VERSION 5.7 ;
  DIVIDERCHAR "/" ;
  BUSBITCHARS "[]" ;
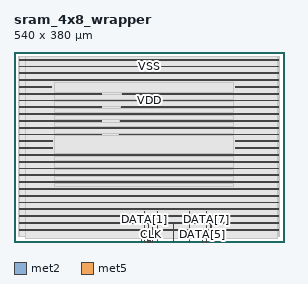
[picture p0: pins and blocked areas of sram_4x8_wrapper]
MACRO sram_4x8_wrapper
  CLASS BLOCK ;
  FOREIGN sram_4x8_wrapper ;
  ORIGIN 0.000 0.000 ;
  SIZE 540.000 BY 380.000 ;
  PIN ADDR[0]
    ANTENNAGATEAREA 0.126000 ;
    DIRECTION INPUT ;
    USE SIGNAL ;
    PORT
      LAYER met2 ;
        RECT 276.160 0.000 276.300 49.680 ;
    END
  END ADDR[0]
  PIN ADDR[1]
    ANTENNAGATEAREA 0.126000 ;
    DIRECTION INPUT ;
    USE SIGNAL ;
    PORT
      LAYER met2 ;
        RECT 269.720 0.000 269.860 49.340 ;
    END
  END ADDR[1]
  PIN CLK
    ANTENNAGATEAREA 2.733000 ;
    DIRECTION INPUT ;
    USE CLOCK ;
    PORT
      LAYER met2 ;
        RECT 273.400 0.000 273.540 6.320 ;
    END
  END CLK
  PIN CSb
    ANTENNAGATEAREA 0.495000 ;
    DIRECTION INPUT ;
    USE SIGNAL ;
    PORT
      LAYER met2 ;
        RECT 270.640 0.000 270.780 12.280 ;
    END
  END CSb
  PIN DATA[0]
    ANTENNAGATEAREA 0.126000 ;
    ANTENNADIFFAREA 1.782000 ;
    DIRECTION INOUT ;
    USE SIGNAL ;
    PORT
      LAYER met2 ;
        RECT 254.080 0.000 254.220 12.650 ;
    END
  END DATA[0]
  PIN DATA[1]
    ANTENNAGATEAREA 0.126000 ;
    ANTENNADIFFAREA 1.782000 ;
    DIRECTION INOUT ;
    USE SIGNAL ;
    PORT
      LAYER met2 ;
        RECT 260.060 0.000 260.200 60.560 ;
    END
  END DATA[1]
  PIN DATA[2]
    ANTENNAGATEAREA 0.126000 ;
    ANTENNADIFFAREA 1.782000 ;
    DIRECTION INOUT ;
    USE SIGNAL ;
    PORT
      LAYER met2 ;
        RECT 286.740 0.000 286.880 61.240 ;
    END
  END DATA[2]
  PIN DATA[3]
    ANTENNAGATEAREA 0.126000 ;
    ANTENNADIFFAREA 1.782000 ;
    DIRECTION INOUT ;
    USE SIGNAL ;
    PORT
      LAYER met2 ;
        RECT 318.940 0.000 319.080 36.420 ;
    END
  END DATA[3]
  PIN DATA[4]
    ANTENNAGATEAREA 0.126000 ;
    ANTENNADIFFAREA 1.782000 ;
    DIRECTION INOUT ;
    USE SIGNAL ;
    PORT
      LAYER met2 ;
        RECT 351.140 0.000 351.280 60.560 ;
    END
  END DATA[4]
  PIN DATA[5]
    ANTENNAGATEAREA 0.126000 ;
    ANTENNADIFFAREA 1.782000 ;
    DIRECTION INOUT ;
    USE SIGNAL ;
    PORT
      LAYER met2 ;
        RECT 376.900 0.000 377.040 9.930 ;
    END
  END DATA[5]
  PIN DATA[6]
    ANTENNAGATEAREA 0.126000 ;
    ANTENNADIFFAREA 1.782000 ;
    DIRECTION INOUT ;
    USE SIGNAL ;
    PORT
      LAYER met2 ;
        RECT 393.920 0.000 394.060 50.360 ;
    END
  END DATA[6]
  PIN DATA[7]
    ANTENNAGATEAREA 0.126000 ;
    ANTENNADIFFAREA 1.782000 ;
    DIRECTION INOUT ;
    USE SIGNAL ;
    PORT
      LAYER met2 ;
        RECT 384.720 0.000 384.860 61.580 ;
    END
  END DATA[7]
  PIN OEb
    ANTENNAGATEAREA 0.373500 ;
    DIRECTION INPUT ;
    USE SIGNAL ;
    PORT
      LAYER met2 ;
        RECT 266.040 0.000 266.180 11.940 ;
    END
  END OEb
  PIN VDD
    ANTENNADIFFAREA 667.750610 ;
    DIRECTION INOUT ;
    USE POWER ;
    PORT
      LAYER met5 ;
        RECT 443.560 309.280 529.920 310.880 ;
    END
    PORT
      LAYER met5 ;
        RECT 442.600 200.480 529.920 202.080 ;
    END
    PORT
      LAYER met5 ;
        RECT 10.120 363.680 529.920 365.280 ;
    END
    PORT
      LAYER met5 ;
        RECT 10.120 336.480 529.920 338.080 ;
    END
    PORT
      LAYER met5 ;
        RECT 10.120 309.280 74.800 310.880 ;
    END
    PORT
      LAYER met5 ;
        RECT 10.120 282.080 529.920 283.680 ;
    END
    PORT
      LAYER met5 ;
        RECT 10.120 254.880 529.920 256.480 ;
    END
    PORT
      LAYER met5 ;
        RECT 10.120 227.680 529.920 229.280 ;
    END
    PORT
      LAYER met5 ;
        RECT 10.120 200.480 76.400 202.080 ;
    END
    PORT
      LAYER met5 ;
        RECT 10.120 173.280 529.920 174.880 ;
    END
    PORT
      LAYER met5 ;
        RECT 10.120 146.080 529.920 147.680 ;
    END
    PORT
      LAYER met5 ;
        RECT 10.120 118.880 529.920 120.480 ;
    END
    PORT
      LAYER met5 ;
        RECT 10.120 91.680 529.920 93.280 ;
    END
    PORT
      LAYER met5 ;
        RECT 10.120 64.480 529.920 66.080 ;
    END
    PORT
      LAYER met5 ;
        RECT 10.120 37.280 529.920 38.880 ;
    END
  END VDD
  PIN VSS
    ANTENNADIFFAREA 597.384949 ;
    DIRECTION INOUT ;
    USE GROUND ;
    PORT
      LAYER met5 ;
        RECT 442.600 186.880 529.920 188.480 ;
    END
    PORT
      LAYER met5 ;
        RECT 216.500 295.680 529.920 297.280 ;
    END
    PORT
      LAYER met5 ;
        RECT 214.500 268.480 529.920 270.080 ;
    END
    PORT
      LAYER met5 ;
        RECT 212.500 241.280 529.920 242.880 ;
    END
    PORT
      LAYER met5 ;
        RECT 210.500 214.080 529.920 215.680 ;
    END
    PORT
      LAYER met5 ;
        RECT 10.120 350.080 529.920 351.680 ;
    END
    PORT
      LAYER met5 ;
        RECT 10.120 322.880 529.920 324.480 ;
    END
    PORT
      LAYER met5 ;
        RECT 10.120 295.680 174.350 297.280 ;
    END
    PORT
      LAYER met5 ;
        RECT 10.120 268.480 174.350 270.080 ;
    END
    PORT
      LAYER met5 ;
        RECT 10.120 241.280 174.350 242.880 ;
    END
    PORT
      LAYER met5 ;
        RECT 10.120 214.080 174.350 215.680 ;
    END
    PORT
      LAYER met5 ;
        RECT 10.120 186.880 76.400 188.480 ;
    END
    PORT
      LAYER met5 ;
        RECT 10.120 159.680 529.920 161.280 ;
    END
    PORT
      LAYER met5 ;
        RECT 10.120 132.480 529.920 134.080 ;
    END
    PORT
      LAYER met5 ;
        RECT 10.120 105.280 529.920 106.880 ;
    END
    PORT
      LAYER met5 ;
        RECT 10.120 78.080 529.920 79.680 ;
    END
    PORT
      LAYER met5 ;
        RECT 10.120 50.880 529.920 52.480 ;
    END
    PORT
      LAYER met5 ;
        RECT 10.120 23.680 529.920 25.280 ;
    END
  END VSS
  PIN WEb
    ANTENNAGATEAREA 0.373500 ;
    DIRECTION INPUT ;
    USE SIGNAL ;
    PORT
      LAYER met2 ;
        RECT 268.800 0.000 268.940 9.930 ;
    END
  END WEb
  OBS
      LAYER nwell ;
        RECT 9.930 10.760 530.110 370.040 ;
      LAYER li1 ;
        RECT 10.120 10.795 529.920 370.005 ;
      LAYER met1 ;
        RECT 10.120 10.640 529.920 370.160 ;
      LAYER met2 ;
        RECT 22.920 61.860 526.550 370.105 ;
        RECT 22.920 61.520 384.440 61.860 ;
        RECT 22.920 60.840 286.460 61.520 ;
        RECT 22.920 12.930 259.780 60.840 ;
        RECT 22.920 6.275 253.800 12.930 ;
        RECT 254.500 6.275 259.780 12.930 ;
        RECT 260.480 49.960 286.460 60.840 ;
        RECT 260.480 49.620 275.880 49.960 ;
        RECT 260.480 12.220 269.440 49.620 ;
        RECT 260.480 6.275 265.760 12.220 ;
        RECT 266.460 10.210 269.440 12.220 ;
        RECT 266.460 6.275 268.520 10.210 ;
        RECT 269.220 6.275 269.440 10.210 ;
        RECT 270.140 12.560 275.880 49.620 ;
        RECT 270.140 6.275 270.360 12.560 ;
        RECT 271.060 6.600 275.880 12.560 ;
        RECT 271.060 6.275 273.120 6.600 ;
        RECT 273.820 6.275 275.880 6.600 ;
        RECT 276.580 6.275 286.460 49.960 ;
        RECT 287.160 60.840 384.440 61.520 ;
        RECT 287.160 36.700 350.860 60.840 ;
        RECT 287.160 6.275 318.660 36.700 ;
        RECT 319.360 6.275 350.860 36.700 ;
        RECT 351.560 10.210 384.440 60.840 ;
        RECT 351.560 6.275 376.620 10.210 ;
        RECT 377.320 6.275 384.440 10.210 ;
        RECT 385.140 50.640 526.550 61.860 ;
        RECT 385.140 6.275 393.640 50.640 ;
        RECT 394.340 6.275 526.550 50.640 ;
      LAYER met3 ;
        RECT 22.900 6.295 526.570 370.085 ;
      LAYER met4 ;
        RECT 22.890 6.295 526.580 370.160 ;
      LAYER met5 ;
        RECT 80.000 298.880 439.000 318.500 ;
        RECT 175.950 294.080 214.900 298.880 ;
        RECT 80.000 285.280 439.000 294.080 ;
        RECT 80.000 271.680 439.000 280.480 ;
        RECT 175.950 266.880 212.900 271.680 ;
        RECT 80.000 258.080 439.000 266.880 ;
        RECT 80.000 244.480 439.000 253.280 ;
        RECT 175.950 239.680 210.900 244.480 ;
        RECT 80.000 230.880 439.000 239.680 ;
        RECT 80.000 217.280 439.000 226.080 ;
        RECT 175.950 212.480 208.900 217.280 ;
        RECT 80.000 176.480 439.000 212.480 ;
        RECT 80.000 162.880 439.000 171.680 ;
        RECT 80.000 149.280 439.000 158.080 ;
        RECT 80.000 135.680 439.000 144.480 ;
        RECT 80.000 122.080 439.000 130.880 ;
        RECT 80.000 111.500 439.000 117.280 ;

  END
END sram_4x8_wrapper
END LIBRARY

